###############################################################
#  Generated by:      Cadence Innovus 21.35-s114_1
#  OS:                Linux x86_64(Host ID pc231.ee.hacettepe.edu.tr)
#  Generated on:      Wed Dec 24 15:45:05 2025
#  Design:            pwm_accelerator_macro
#  Command:           write_lef_abstract -5.7 outputs/pwm_accelerator_macro/pwm_accelerator_macro.lef
###############################################################

VERSION 5.7 ;

BUSBITCHARS "[]" ;
DIVIDERCHAR "/" ;

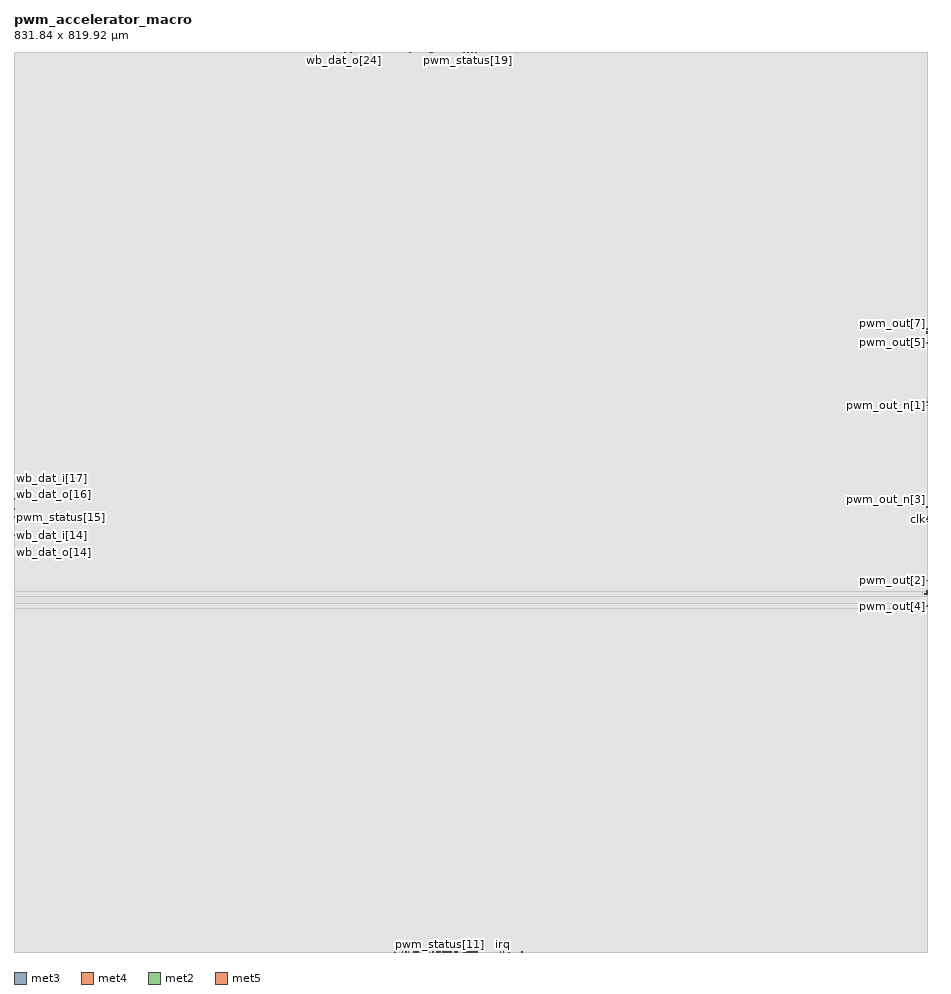
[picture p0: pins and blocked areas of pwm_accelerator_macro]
MACRO pwm_accelerator_macro
  CLASS BLOCK ;
  SIZE 831.840000 BY 819.920000 ;
  FOREIGN pwm_accelerator_macro 0.000000 0.000000 ;
  ORIGIN 0 0 ;
  SYMMETRY X Y R90 ;
  PIN clk
    DIRECTION INPUT ;
    USE SIGNAL ;
    PORT
      LAYER met3 ;
        RECT 831.040000 393.670000 831.840000 393.970000 ;
    END
  END clk
  PIN rst_n
    DIRECTION INPUT ;
    USE SIGNAL ;
    PORT
      LAYER met3 ;
        RECT 831.040000 394.890000 831.840000 395.190000 ;
    END
  END rst_n
  PIN wb_adr_i[31]
    DIRECTION INPUT ;
    USE SIGNAL ;
    PORT
      LAYER met4 ;
        RECT 413.370000 819.120000 413.670000 819.920000 ;
    END
  END wb_adr_i[31]
  PIN wb_adr_i[30]
    DIRECTION INPUT ;
    USE SIGNAL ;
    PORT
      LAYER met4 ;
        RECT 413.370000 0.000000 413.670000 0.800000 ;
    END
  END wb_adr_i[30]
  PIN wb_adr_i[29]
    DIRECTION INPUT ;
    USE SIGNAL ;
    PORT
      LAYER met4 ;
        RECT 418.290000 819.120000 418.590000 819.920000 ;
    END
  END wb_adr_i[29]
  PIN wb_adr_i[28]
    DIRECTION INPUT ;
    USE SIGNAL ;
    PORT
      LAYER met4 ;
        RECT 418.290000 0.000000 418.590000 0.800000 ;
    END
  END wb_adr_i[28]
  PIN wb_adr_i[27]
    DIRECTION INPUT ;
    USE SIGNAL ;
    PORT
      LAYER met2 ;
        RECT 412.970000 819.435000 413.110000 819.920000 ;
    END
  END wb_adr_i[27]
  PIN wb_adr_i[26]
    DIRECTION INPUT ;
    USE SIGNAL ;
    PORT
      LAYER met2 ;
        RECT 418.730000 819.435000 418.870000 819.920000 ;
    END
  END wb_adr_i[26]
  PIN wb_adr_i[25]
    DIRECTION INPUT ;
    USE SIGNAL ;
    PORT
      LAYER met2 ;
        RECT 412.970000 0.000000 413.110000 0.485000 ;
    END
  END wb_adr_i[25]
  PIN wb_adr_i[24]
    DIRECTION INPUT ;
    USE SIGNAL ;
    PORT
      LAYER met2 ;
        RECT 418.730000 0.000000 418.870000 0.485000 ;
    END
  END wb_adr_i[24]
  PIN wb_adr_i[23]
    DIRECTION INPUT ;
    USE SIGNAL ;
    PORT
      LAYER met2 ;
        RECT 412.010000 819.435000 412.150000 819.920000 ;
    END
  END wb_adr_i[23]
  PIN wb_adr_i[22]
    DIRECTION INPUT ;
    USE SIGNAL ;
    PORT
      LAYER met4 ;
        RECT 412.140000 819.120000 412.440000 819.920000 ;
    END
  END wb_adr_i[22]
  PIN wb_adr_i[21]
    DIRECTION INPUT ;
    USE SIGNAL ;
    PORT
      LAYER met2 ;
        RECT 412.010000 0.000000 412.150000 0.485000 ;
    END
  END wb_adr_i[21]
  PIN wb_adr_i[20]
    DIRECTION INPUT ;
    USE SIGNAL ;
    PORT
      LAYER met4 ;
        RECT 412.140000 0.000000 412.440000 0.800000 ;
    END
  END wb_adr_i[20]
  PIN wb_adr_i[19]
    DIRECTION INPUT ;
    USE SIGNAL ;
    PORT
      LAYER met2 ;
        RECT 419.690000 819.435000 419.830000 819.920000 ;
    END
  END wb_adr_i[19]
  PIN wb_adr_i[18]
    DIRECTION INPUT ;
    USE SIGNAL ;
    PORT
      LAYER met4 ;
        RECT 419.520000 819.120000 419.820000 819.920000 ;
    END
  END wb_adr_i[18]
  PIN wb_adr_i[17]
    DIRECTION INPUT ;
    USE SIGNAL ;
    PORT
      LAYER met2 ;
        RECT 419.690000 0.000000 419.830000 0.485000 ;
    END
  END wb_adr_i[17]
  PIN wb_adr_i[16]
    DIRECTION INPUT ;
    USE SIGNAL ;
    PORT
      LAYER met4 ;
        RECT 419.520000 0.000000 419.820000 0.800000 ;
    END
  END wb_adr_i[16]
  PIN wb_adr_i[15]
    DIRECTION INPUT ;
    USE SIGNAL ;
    PORT
      LAYER met2 ;
        RECT 411.050000 819.435000 411.190000 819.920000 ;
    END
  END wb_adr_i[15]
  PIN wb_adr_i[14]
    DIRECTION INPUT ;
    USE SIGNAL ;
    PORT
      LAYER met2 ;
        RECT 420.650000 819.435000 420.790000 819.920000 ;
    END
  END wb_adr_i[14]
  PIN wb_adr_i[13]
    DIRECTION INPUT ;
    USE SIGNAL ;
    PORT
      LAYER met2 ;
        RECT 411.050000 0.000000 411.190000 0.485000 ;
    END
  END wb_adr_i[13]
  PIN wb_adr_i[12]
    DIRECTION INPUT ;
    USE SIGNAL ;
    PORT
      LAYER met2 ;
        RECT 420.650000 0.000000 420.790000 0.485000 ;
    END
  END wb_adr_i[12]
  PIN wb_adr_i[11]
    DIRECTION INPUT ;
    USE SIGNAL ;
    PORT
      LAYER met4 ;
        RECT 410.910000 819.120000 411.210000 819.920000 ;
    END
  END wb_adr_i[11]
  PIN wb_adr_i[10]
    DIRECTION INPUT ;
    USE SIGNAL ;
    PORT
      LAYER met4 ;
        RECT 410.910000 0.000000 411.210000 0.800000 ;
    END
  END wb_adr_i[10]
  PIN wb_adr_i[9]
    DIRECTION INPUT ;
    USE SIGNAL ;
    PORT
      LAYER met4 ;
        RECT 420.750000 819.120000 421.050000 819.920000 ;
    END
  END wb_adr_i[9]
  PIN wb_adr_i[8]
    DIRECTION INPUT ;
    USE SIGNAL ;
    PORT
      LAYER met4 ;
        RECT 420.750000 0.000000 421.050000 0.800000 ;
    END
  END wb_adr_i[8]
  PIN wb_adr_i[7]
    DIRECTION INPUT ;
    USE SIGNAL ;
    PORT
      LAYER met2 ;
        RECT 403.370000 0.000000 403.510000 0.485000 ;
    END
  END wb_adr_i[7]
  PIN wb_adr_i[6]
    DIRECTION INPUT ;
    USE SIGNAL ;
    PORT
      LAYER met2 ;
        RECT 410.090000 0.000000 410.230000 0.485000 ;
    END
  END wb_adr_i[6]
  PIN wb_adr_i[5]
    DIRECTION INPUT ;
    USE SIGNAL ;
    PORT
      LAYER met4 ;
        RECT 402.915000 0.000000 403.215000 0.800000 ;
    END
  END wb_adr_i[5]
  PIN wb_adr_i[4]
    DIRECTION INPUT ;
    USE SIGNAL ;
    PORT
      LAYER met4 ;
        RECT 409.680000 0.000000 409.980000 0.800000 ;
    END
  END wb_adr_i[4]
  PIN wb_adr_i[3]
    DIRECTION INPUT ;
    USE SIGNAL ;
    PORT
      LAYER met2 ;
        RECT 402.410000 0.000000 402.550000 0.485000 ;
    END
  END wb_adr_i[3]
  PIN wb_adr_i[2]
    DIRECTION INPUT ;
    USE SIGNAL ;
    PORT
      LAYER met4 ;
        RECT 394.920000 0.000000 395.220000 0.800000 ;
    END
  END wb_adr_i[2]
  PIN wb_adr_i[1]
    DIRECTION INPUT ;
    USE SIGNAL ;
    PORT
      LAYER met2 ;
        RECT 410.090000 819.435000 410.230000 819.920000 ;
    END
  END wb_adr_i[1]
  PIN wb_adr_i[0]
    DIRECTION INPUT ;
    USE SIGNAL ;
    PORT
      LAYER met2 ;
        RECT 421.610000 819.435000 421.750000 819.920000 ;
    END
  END wb_adr_i[0]
  PIN wb_dat_o[31]
    DIRECTION OUTPUT ;
    USE SIGNAL ;
    PORT
      LAYER met2 ;
        RECT 369.290000 819.435000 369.430000 819.920000 ;
    END
  END wb_dat_o[31]
  PIN wb_dat_o[30]
    DIRECTION OUTPUT ;
    USE SIGNAL ;
    PORT
      LAYER met2 ;
        RECT 306.890000 819.435000 307.030000 819.920000 ;
    END
  END wb_dat_o[30]
  PIN wb_dat_o[29]
    DIRECTION OUTPUT ;
    USE SIGNAL ;
    PORT
      LAYER met2 ;
        RECT 301.130000 819.435000 301.270000 819.920000 ;
    END
  END wb_dat_o[29]
  PIN wb_dat_o[28]
    DIRECTION OUTPUT ;
    USE SIGNAL ;
    PORT
      LAYER met2 ;
        RECT 312.650000 819.435000 312.790000 819.920000 ;
    END
  END wb_dat_o[28]
  PIN wb_dat_o[27]
    DIRECTION OUTPUT ;
    USE SIGNAL ;
    PORT
      LAYER met4 ;
        RECT 311.895000 819.120000 312.195000 819.920000 ;
    END
  END wb_dat_o[27]
  PIN wb_dat_o[26]
    DIRECTION OUTPUT ;
    USE SIGNAL ;
    PORT
      LAYER met2 ;
        RECT 304.010000 819.435000 304.150000 819.920000 ;
    END
  END wb_dat_o[26]
  PIN wb_dat_o[25]
    DIRECTION OUTPUT ;
    USE SIGNAL ;
    PORT
      LAYER met4 ;
        RECT 301.440000 819.120000 301.740000 819.920000 ;
    END
  END wb_dat_o[25]
  PIN wb_dat_o[24]
    DIRECTION OUTPUT ;
    USE SIGNAL ;
    PORT
      LAYER met2 ;
        RECT 300.170000 819.435000 300.310000 819.920000 ;
    END
  END wb_dat_o[24]
  PIN wb_dat_o[23]
    DIRECTION OUTPUT ;
    USE SIGNAL ;
    PORT
      LAYER met2 ;
        RECT 365.930000 819.435000 366.070000 819.920000 ;
    END
  END wb_dat_o[23]
  PIN wb_dat_o[22]
    DIRECTION OUTPUT ;
    USE SIGNAL ;
    PORT
      LAYER met2 ;
        RECT 371.210000 819.435000 371.350000 819.920000 ;
    END
  END wb_dat_o[22]
  PIN wb_dat_o[21]
    DIRECTION OUTPUT ;
    USE SIGNAL ;
    PORT
      LAYER met2 ;
        RECT 362.090000 819.435000 362.230000 819.920000 ;
    END
  END wb_dat_o[21]
  PIN wb_dat_o[20]
    DIRECTION OUTPUT ;
    USE SIGNAL ;
    PORT
      LAYER met2 ;
        RECT 361.130000 819.435000 361.270000 819.920000 ;
    END
  END wb_dat_o[20]
  PIN wb_dat_o[19]
    DIRECTION OUTPUT ;
    USE SIGNAL ;
    PORT
      LAYER met2 ;
        RECT 366.890000 819.435000 367.030000 819.920000 ;
    END
  END wb_dat_o[19]
  PIN wb_dat_o[18]
    DIRECTION OUTPUT ;
    USE SIGNAL ;
    PORT
      LAYER met4 ;
        RECT 360.480000 819.120000 360.780000 819.920000 ;
    END
  END wb_dat_o[18]
  PIN wb_dat_o[17]
    DIRECTION OUTPUT ;
    USE SIGNAL ;
    PORT
      LAYER met3 ;
        RECT 0.000000 435.760000 0.800000 436.060000 ;
    END
  END wb_dat_o[17]
  PIN wb_dat_o[16]
    DIRECTION OUTPUT ;
    USE SIGNAL ;
    PORT
      LAYER met3 ;
        RECT 0.000000 416.850000 0.800000 417.150000 ;
    END
  END wb_dat_o[16]
  PIN wb_dat_o[15]
    DIRECTION OUTPUT ;
    USE SIGNAL ;
    PORT
      LAYER met3 ;
        RECT 0.000000 393.670000 0.800000 393.970000 ;
    END
  END wb_dat_o[15]
  PIN wb_dat_o[14]
    DIRECTION OUTPUT ;
    USE SIGNAL ;
    PORT
      LAYER met3 ;
        RECT 0.000000 363.780000 0.800000 364.080000 ;
    END
  END wb_dat_o[14]
  PIN wb_dat_o[13]
    DIRECTION OUTPUT ;
    USE SIGNAL ;
    PORT
      LAYER met2 ;
        RECT 373.610000 0.000000 373.750000 0.485000 ;
    END
  END wb_dat_o[13]
  PIN wb_dat_o[12]
    DIRECTION OUTPUT ;
    USE SIGNAL ;
    PORT
      LAYER met2 ;
        RECT 382.250000 0.000000 382.390000 0.485000 ;
    END
  END wb_dat_o[12]
  PIN wb_dat_o[11]
    DIRECTION OUTPUT ;
    USE SIGNAL ;
    PORT
      LAYER met2 ;
        RECT 374.570000 0.000000 374.710000 0.485000 ;
    END
  END wb_dat_o[11]
  PIN wb_dat_o[10]
    DIRECTION OUTPUT ;
    USE SIGNAL ;
    PORT
      LAYER met2 ;
        RECT 370.730000 0.000000 370.870000 0.485000 ;
    END
  END wb_dat_o[10]
  PIN wb_dat_o[9]
    DIRECTION OUTPUT ;
    USE SIGNAL ;
    PORT
      LAYER met2 ;
        RECT 376.490000 0.000000 376.630000 0.485000 ;
    END
  END wb_dat_o[9]
  PIN wb_dat_o[8]
    DIRECTION OUTPUT ;
    USE SIGNAL ;
    PORT
      LAYER met2 ;
        RECT 378.410000 0.000000 378.550000 0.485000 ;
    END
  END wb_dat_o[8]
  PIN wb_dat_o[7]
    DIRECTION OUTPUT ;
    USE SIGNAL ;
    PORT
      LAYER met2 ;
        RECT 372.650000 0.000000 372.790000 0.485000 ;
    END
  END wb_dat_o[7]
  PIN wb_dat_o[6]
    DIRECTION OUTPUT ;
    USE SIGNAL ;
    PORT
      LAYER met2 ;
        RECT 366.410000 0.000000 366.550000 0.485000 ;
    END
  END wb_dat_o[6]
  PIN wb_dat_o[5]
    DIRECTION OUTPUT ;
    USE SIGNAL ;
    PORT
      LAYER met4 ;
        RECT 365.400000 0.000000 365.700000 0.800000 ;
    END
  END wb_dat_o[5]
  PIN wb_dat_o[4]
    DIRECTION OUTPUT ;
    USE SIGNAL ;
    PORT
      LAYER met2 ;
        RECT 364.010000 0.000000 364.150000 0.485000 ;
    END
  END wb_dat_o[4]
  PIN wb_dat_o[3]
    DIRECTION OUTPUT ;
    USE SIGNAL ;
    PORT
      LAYER met4 ;
        RECT 356.790000 0.000000 357.090000 0.800000 ;
    END
  END wb_dat_o[3]
  PIN wb_dat_o[2]
    DIRECTION OUTPUT ;
    USE SIGNAL ;
    PORT
      LAYER met4 ;
        RECT 372.165000 0.000000 372.465000 0.800000 ;
    END
  END wb_dat_o[2]
  PIN wb_dat_o[1]
    DIRECTION OUTPUT ;
    USE SIGNAL ;
    PORT
      LAYER met4 ;
        RECT 376.470000 0.000000 376.770000 0.800000 ;
    END
  END wb_dat_o[1]
  PIN wb_dat_o[0]
    DIRECTION OUTPUT ;
    USE SIGNAL ;
    PORT
      LAYER met4 ;
        RECT 364.170000 0.000000 364.470000 0.800000 ;
    END
  END wb_dat_o[0]
  PIN wb_dat_i[31]
    DIRECTION INPUT ;
    USE SIGNAL ;
    PORT
      LAYER met2 ;
        RECT 377.930000 819.435000 378.070000 819.920000 ;
    END
  END wb_dat_i[31]
  PIN wb_dat_i[30]
    DIRECTION INPUT ;
    USE SIGNAL ;
    PORT
      LAYER met4 ;
        RECT 377.700000 819.120000 378.000000 819.920000 ;
    END
  END wb_dat_i[30]
  PIN wb_dat_i[29]
    DIRECTION INPUT ;
    USE SIGNAL ;
    PORT
      LAYER met2 ;
        RECT 379.370000 819.435000 379.510000 819.920000 ;
    END
  END wb_dat_i[29]
  PIN wb_dat_i[28]
    DIRECTION INPUT ;
    USE SIGNAL ;
    PORT
      LAYER met2 ;
        RECT 381.290000 819.435000 381.430000 819.920000 ;
    END
  END wb_dat_i[28]
  PIN wb_dat_i[27]
    DIRECTION INPUT ;
    USE SIGNAL ;
    PORT
      LAYER met4 ;
        RECT 378.930000 819.120000 379.230000 819.920000 ;
    END
  END wb_dat_i[27]
  PIN wb_dat_i[26]
    DIRECTION INPUT ;
    USE SIGNAL ;
    PORT
      LAYER met4 ;
        RECT 380.775000 819.120000 381.075000 819.920000 ;
    END
  END wb_dat_i[26]
  PIN wb_dat_i[25]
    DIRECTION INPUT ;
    USE SIGNAL ;
    PORT
      LAYER met2 ;
        RECT 376.970000 819.435000 377.110000 819.920000 ;
    END
  END wb_dat_i[25]
  PIN wb_dat_i[24]
    DIRECTION INPUT ;
    USE SIGNAL ;
    PORT
      LAYER met2 ;
        RECT 380.330000 819.435000 380.470000 819.920000 ;
    END
  END wb_dat_i[24]
  PIN wb_dat_i[23]
    DIRECTION INPUT ;
    USE SIGNAL ;
    PORT
      LAYER met4 ;
        RECT 376.470000 819.120000 376.770000 819.920000 ;
    END
  END wb_dat_i[23]
  PIN wb_dat_i[22]
    DIRECTION INPUT ;
    USE SIGNAL ;
    PORT
      LAYER met2 ;
        RECT 394.250000 819.435000 394.390000 819.920000 ;
    END
  END wb_dat_i[22]
  PIN wb_dat_i[21]
    DIRECTION INPUT ;
    USE SIGNAL ;
    PORT
      LAYER met2 ;
        RECT 372.170000 819.435000 372.310000 819.920000 ;
    END
  END wb_dat_i[21]
  PIN wb_dat_i[20]
    DIRECTION INPUT ;
    USE SIGNAL ;
    PORT
      LAYER met4 ;
        RECT 372.165000 819.120000 372.465000 819.920000 ;
    END
  END wb_dat_i[20]
  PIN wb_dat_i[19]
    DIRECTION INPUT ;
    USE SIGNAL ;
    PORT
      LAYER met2 ;
        RECT 373.610000 819.435000 373.750000 819.920000 ;
    END
  END wb_dat_i[19]
  PIN wb_dat_i[18]
    DIRECTION INPUT ;
    USE SIGNAL ;
    PORT
      LAYER met2 ;
        RECT 375.530000 819.435000 375.670000 819.920000 ;
    END
  END wb_dat_i[18]
  PIN wb_dat_i[17]
    DIRECTION INPUT ;
    USE SIGNAL ;
    PORT
      LAYER met3 ;
        RECT 0.000000 431.490000 0.800000 431.790000 ;
    END
  END wb_dat_i[17]
  PIN wb_dat_i[16]
    DIRECTION INPUT ;
    USE SIGNAL ;
    PORT
      LAYER met3 ;
        RECT 0.000000 412.580000 0.800000 412.880000 ;
    END
  END wb_dat_i[16]
  PIN wb_dat_i[15]
    DIRECTION INPUT ;
    USE SIGNAL ;
    PORT
      LAYER met3 ;
        RECT 0.000000 403.430000 0.800000 403.730000 ;
    END
  END wb_dat_i[15]
  PIN wb_dat_i[14]
    DIRECTION INPUT ;
    USE SIGNAL ;
    PORT
      LAYER met3 ;
        RECT 0.000000 379.640000 0.800000 379.940000 ;
    END
  END wb_dat_i[14]
  PIN wb_dat_i[13]
    DIRECTION INPUT ;
    USE SIGNAL ;
    PORT
      LAYER met2 ;
        RECT 409.130000 0.000000 409.270000 0.485000 ;
    END
  END wb_dat_i[13]
  PIN wb_dat_i[12]
    DIRECTION INPUT ;
    USE SIGNAL ;
    PORT
      LAYER met2 ;
        RECT 404.330000 0.000000 404.470000 0.485000 ;
    END
  END wb_dat_i[12]
  PIN wb_dat_i[11]
    DIRECTION INPUT ;
    USE SIGNAL ;
    PORT
      LAYER met2 ;
        RECT 367.370000 0.000000 367.510000 0.485000 ;
    END
  END wb_dat_i[11]
  PIN wb_dat_i[10]
    DIRECTION INPUT ;
    USE SIGNAL ;
    PORT
      LAYER met2 ;
        RECT 364.970000 0.000000 365.110000 0.485000 ;
    END
  END wb_dat_i[10]
  PIN wb_dat_i[9]
    DIRECTION INPUT ;
    USE SIGNAL ;
    PORT
      LAYER met4 ;
        RECT 366.630000 0.000000 366.930000 0.800000 ;
    END
  END wb_dat_i[9]
  PIN wb_dat_i[8]
    DIRECTION INPUT ;
    USE SIGNAL ;
    PORT
      LAYER met4 ;
        RECT 367.860000 0.000000 368.160000 0.800000 ;
    END
  END wb_dat_i[8]
  PIN wb_dat_i[7]
    DIRECTION INPUT ;
    USE SIGNAL ;
    PORT
      LAYER met2 ;
        RECT 359.210000 0.000000 359.350000 0.485000 ;
    END
  END wb_dat_i[7]
  PIN wb_dat_i[6]
    DIRECTION INPUT ;
    USE SIGNAL ;
    PORT
      LAYER met2 ;
        RECT 347.690000 0.000000 347.830000 0.485000 ;
    END
  END wb_dat_i[6]
  PIN wb_dat_i[5]
    DIRECTION INPUT ;
    USE SIGNAL ;
    PORT
      LAYER met2 ;
        RECT 357.290000 0.000000 357.430000 0.485000 ;
    END
  END wb_dat_i[5]
  PIN wb_dat_i[4]
    DIRECTION INPUT ;
    USE SIGNAL ;
    PORT
      LAYER met2 ;
        RECT 346.250000 0.000000 346.390000 0.485000 ;
    END
  END wb_dat_i[4]
  PIN wb_dat_i[3]
    DIRECTION INPUT ;
    USE SIGNAL ;
    PORT
      LAYER met2 ;
        RECT 353.930000 0.000000 354.070000 0.485000 ;
    END
  END wb_dat_i[3]
  PIN wb_dat_i[2]
    DIRECTION INPUT ;
    USE SIGNAL ;
    PORT
      LAYER met2 ;
        RECT 462.890000 0.000000 463.030000 0.485000 ;
    END
  END wb_dat_i[2]
  PIN wb_dat_i[1]
    DIRECTION INPUT ;
    USE SIGNAL ;
    PORT
      LAYER met2 ;
        RECT 461.930000 0.000000 462.070000 0.485000 ;
    END
  END wb_dat_i[1]
  PIN wb_dat_i[0]
    DIRECTION INPUT ;
    USE SIGNAL ;
    PORT
      LAYER met2 ;
        RECT 443.210000 0.000000 443.350000 0.485000 ;
    END
  END wb_dat_i[0]
  PIN wb_we_i
    DIRECTION INPUT ;
    USE SIGNAL ;
    PORT
      LAYER met2 ;
        RECT 398.090000 0.000000 398.230000 0.485000 ;
    END
  END wb_we_i
  PIN wb_sel_i[3]
    DIRECTION INPUT ;
    USE SIGNAL ;
    PORT
      LAYER met2 ;
        RECT 421.610000 0.000000 421.750000 0.485000 ;
    END
  END wb_sel_i[3]
  PIN wb_sel_i[2]
    DIRECTION INPUT ;
    USE SIGNAL ;
    PORT
      LAYER met4 ;
        RECT 409.680000 819.120000 409.980000 819.920000 ;
    END
  END wb_sel_i[2]
  PIN wb_sel_i[1]
    DIRECTION INPUT ;
    USE SIGNAL ;
    PORT
      LAYER met4 ;
        RECT 421.980000 819.120000 422.280000 819.920000 ;
    END
  END wb_sel_i[1]
  PIN wb_sel_i[0]
    DIRECTION INPUT ;
    USE SIGNAL ;
    PORT
      LAYER met4 ;
        RECT 421.980000 0.000000 422.280000 0.800000 ;
    END
  END wb_sel_i[0]
  PIN wb_cyc_i
    DIRECTION INPUT ;
    USE SIGNAL ;
    PORT
      LAYER met2 ;
        RECT 400.970000 0.000000 401.110000 0.485000 ;
    END
  END wb_cyc_i
  PIN wb_stb_i
    DIRECTION INPUT ;
    USE SIGNAL ;
    PORT
      LAYER met4 ;
        RECT 386.310000 0.000000 386.610000 0.800000 ;
    END
  END wb_stb_i
  PIN wb_ack_o
    DIRECTION OUTPUT ;
    USE SIGNAL ;
    PORT
      LAYER met4 ;
        RECT 370.935000 0.000000 371.235000 0.800000 ;
    END
  END wb_ack_o
  PIN wb_err_o
    DIRECTION OUTPUT ;
    USE SIGNAL ;
    PORT
      LAYER met3 ;
        RECT 0.000000 409.530000 0.800000 409.830000 ;
    END
  END wb_err_o
  PIN pwm_out[7]
    DIRECTION OUTPUT ;
    USE SIGNAL ;
    PORT
      LAYER met3 ;
        RECT 831.040000 565.080000 831.840000 565.380000 ;
    END
  END pwm_out[7]
  PIN pwm_out[6]
    DIRECTION OUTPUT ;
    USE SIGNAL ;
    PORT
      LAYER met3 ;
        RECT 831.040000 327.790000 831.840000 328.090000 ;
    END
  END pwm_out[6]
  PIN pwm_out[5]
    DIRECTION OUTPUT ;
    USE SIGNAL ;
    PORT
      LAYER met3 ;
        RECT 831.040000 554.710000 831.840000 555.010000 ;
    END
  END pwm_out[5]
  PIN pwm_out[4]
    DIRECTION OUTPUT ;
    USE SIGNAL ;
    PORT
      LAYER met3 ;
        RECT 831.040000 314.980000 831.840000 315.280000 ;
    END
  END pwm_out[4]
  PIN pwm_out[3]
    DIRECTION OUTPUT ;
    USE SIGNAL ;
    PORT
      LAYER met3 ;
        RECT 831.040000 391.840000 831.840000 392.140000 ;
    END
  END pwm_out[3]
  PIN pwm_out[2]
    DIRECTION OUTPUT ;
    USE SIGNAL ;
    PORT
      LAYER met3 ;
        RECT 831.040000 338.160000 831.840000 338.460000 ;
    END
  END pwm_out[2]
  PIN pwm_out[1]
    DIRECTION OUTPUT ;
    USE SIGNAL ;
    PORT
      LAYER met3 ;
        RECT 831.040000 501.030000 831.840000 501.330000 ;
    END
  END pwm_out[1]
  PIN pwm_out[0]
    DIRECTION OUTPUT ;
    USE SIGNAL ;
    PORT
      LAYER met5 ;
        RECT 829.340000 314.330000 831.840000 315.930000 ;
    END
  END pwm_out[0]
  PIN pwm_out_n[7]
    DIRECTION OUTPUT ;
    USE SIGNAL ;
    PORT
      LAYER met3 ;
        RECT 831.040000 563.860000 831.840000 564.160000 ;
    END
  END pwm_out_n[7]
  PIN pwm_out_n[6]
    DIRECTION OUTPUT ;
    USE SIGNAL ;
    PORT
      LAYER met3 ;
        RECT 831.040000 325.350000 831.840000 325.650000 ;
    END
  END pwm_out_n[6]
  PIN pwm_out_n[5]
    DIRECTION OUTPUT ;
    USE SIGNAL ;
    PORT
      LAYER met3 ;
        RECT 831.040000 567.520000 831.840000 567.820000 ;
    END
  END pwm_out_n[5]
  PIN pwm_out_n[4]
    DIRECTION OUTPUT ;
    USE SIGNAL ;
    PORT
      LAYER met3 ;
        RECT 831.040000 329.010000 831.840000 329.310000 ;
    END
  END pwm_out_n[4]
  PIN pwm_out_n[3]
    DIRECTION OUTPUT ;
    USE SIGNAL ;
    PORT
      LAYER met3 ;
        RECT 831.040000 405.260000 831.840000 405.560000 ;
    END
  END pwm_out_n[3]
  PIN pwm_out_n[2]
    DIRECTION OUTPUT ;
    USE SIGNAL ;
    PORT
      LAYER met3 ;
        RECT 831.040000 326.570000 831.840000 326.870000 ;
    END
  END pwm_out_n[2]
  PIN pwm_out_n[1]
    DIRECTION OUTPUT ;
    USE SIGNAL ;
    PORT
      LAYER met3 ;
        RECT 831.040000 497.980000 831.840000 498.280000 ;
    END
  END pwm_out_n[1]
  PIN pwm_out_n[0]
    DIRECTION OUTPUT ;
    USE SIGNAL ;
    PORT
      LAYER met5 ;
        RECT 829.340000 325.310000 831.840000 326.910000 ;
    END
  END pwm_out_n[0]
  PIN irq
    DIRECTION OUTPUT ;
    USE SIGNAL ;
    PORT
      LAYER met2 ;
        RECT 445.610000 0.000000 445.750000 0.485000 ;
    END
  END irq
  PIN pwm_sync_out
    DIRECTION OUTPUT ;
    USE SIGNAL ;
    PORT
      LAYER met2 ;
        RECT 450.890000 0.000000 451.030000 0.485000 ;
    END
  END pwm_sync_out
  PIN pwm_sync_in
    DIRECTION INPUT ;
    USE SIGNAL ;
    PORT
      LAYER met3 ;
        RECT 831.040000 396.110000 831.840000 396.410000 ;
    END
  END pwm_sync_in
  PIN pwm_status[31]
    DIRECTION OUTPUT ;
    USE SIGNAL ;
    PORT
      LAYER met2 ;
        RECT 415.850000 819.435000 415.990000 819.920000 ;
    END
  END pwm_status[31]
  PIN pwm_status[30]
    DIRECTION OUTPUT ;
    USE SIGNAL ;
    PORT
      LAYER met2 ;
        RECT 415.850000 0.000000 415.990000 0.485000 ;
    END
  END pwm_status[30]
  PIN pwm_status[29]
    DIRECTION OUTPUT ;
    USE SIGNAL ;
    PORT
      LAYER met4 ;
        RECT 415.830000 819.120000 416.130000 819.920000 ;
    END
  END pwm_status[29]
  PIN pwm_status[28]
    DIRECTION OUTPUT ;
    USE SIGNAL ;
    PORT
      LAYER met4 ;
        RECT 415.830000 0.000000 416.130000 0.800000 ;
    END
  END pwm_status[28]
  PIN pwm_status[27]
    DIRECTION OUTPUT ;
    USE SIGNAL ;
    PORT
      LAYER met2 ;
        RECT 414.890000 819.435000 415.030000 819.920000 ;
    END
  END pwm_status[27]
  PIN pwm_status[26]
    DIRECTION OUTPUT ;
    USE SIGNAL ;
    PORT
      LAYER met2 ;
        RECT 416.810000 819.435000 416.950000 819.920000 ;
    END
  END pwm_status[26]
  PIN pwm_status[25]
    DIRECTION OUTPUT ;
    USE SIGNAL ;
    PORT
      LAYER met2 ;
        RECT 414.890000 0.000000 415.030000 0.485000 ;
    END
  END pwm_status[25]
  PIN pwm_status[24]
    DIRECTION OUTPUT ;
    USE SIGNAL ;
    PORT
      LAYER met2 ;
        RECT 416.810000 0.000000 416.950000 0.485000 ;
    END
  END pwm_status[24]
  PIN pwm_status[23]
    DIRECTION OUTPUT ;
    USE SIGNAL ;
    PORT
      LAYER met4 ;
        RECT 414.600000 819.120000 414.900000 819.920000 ;
    END
  END pwm_status[23]
  PIN pwm_status[22]
    DIRECTION OUTPUT ;
    USE SIGNAL ;
    PORT
      LAYER met4 ;
        RECT 414.600000 0.000000 414.900000 0.800000 ;
    END
  END pwm_status[22]
  PIN pwm_status[21]
    DIRECTION OUTPUT ;
    USE SIGNAL ;
    PORT
      LAYER met4 ;
        RECT 417.060000 819.120000 417.360000 819.920000 ;
    END
  END pwm_status[21]
  PIN pwm_status[20]
    DIRECTION OUTPUT ;
    USE SIGNAL ;
    PORT
      LAYER met4 ;
        RECT 417.060000 0.000000 417.360000 0.800000 ;
    END
  END pwm_status[20]
  PIN pwm_status[19]
    DIRECTION OUTPUT ;
    USE SIGNAL ;
    PORT
      LAYER met2 ;
        RECT 413.930000 819.435000 414.070000 819.920000 ;
    END
  END pwm_status[19]
  PIN pwm_status[18]
    DIRECTION OUTPUT ;
    USE SIGNAL ;
    PORT
      LAYER met2 ;
        RECT 417.770000 819.435000 417.910000 819.920000 ;
    END
  END pwm_status[18]
  PIN pwm_status[17]
    DIRECTION OUTPUT ;
    USE SIGNAL ;
    PORT
      LAYER met2 ;
        RECT 413.930000 0.000000 414.070000 0.485000 ;
    END
  END pwm_status[17]
  PIN pwm_status[16]
    DIRECTION OUTPUT ;
    USE SIGNAL ;
    PORT
      LAYER met2 ;
        RECT 417.770000 0.000000 417.910000 0.485000 ;
    END
  END pwm_status[16]
  PIN pwm_status[15]
    DIRECTION OUTPUT ;
    USE SIGNAL ;
    PORT
      LAYER met3 ;
        RECT 0.000000 396.110000 0.800000 396.410000 ;
    END
  END pwm_status[15]
  PIN pwm_status[14]
    DIRECTION OUTPUT ;
    USE SIGNAL ;
    PORT
      LAYER met2 ;
        RECT 391.850000 0.000000 391.990000 0.485000 ;
    END
  END pwm_status[14]
  PIN pwm_status[13]
    DIRECTION OUTPUT ;
    USE SIGNAL ;
    PORT
      LAYER met2 ;
        RECT 394.250000 0.000000 394.390000 0.485000 ;
    END
  END pwm_status[13]
  PIN pwm_status[12]
    DIRECTION OUTPUT ;
    USE SIGNAL ;
    PORT
      LAYER met2 ;
        RECT 392.810000 0.000000 392.950000 0.485000 ;
    END
  END pwm_status[12]
  PIN pwm_status[11]
    DIRECTION OUTPUT ;
    USE SIGNAL ;
    PORT
      LAYER met2 ;
        RECT 388.010000 0.000000 388.150000 0.485000 ;
    END
  END pwm_status[11]
  PIN pwm_status[10]
    DIRECTION OUTPUT ;
    USE SIGNAL ;
    PORT
      LAYER met2 ;
        RECT 384.650000 0.000000 384.790000 0.485000 ;
    END
  END pwm_status[10]
  PIN pwm_status[9]
    DIRECTION OUTPUT ;
    USE SIGNAL ;
    PORT
      LAYER met2 ;
        RECT 386.090000 0.000000 386.230000 0.485000 ;
    END
  END pwm_status[9]
  PIN pwm_status[8]
    DIRECTION OUTPUT ;
    USE SIGNAL ;
    PORT
      LAYER met4 ;
        RECT 385.080000 0.000000 385.380000 0.800000 ;
    END
  END pwm_status[8]
  PIN pwm_status[7]
    DIRECTION OUTPUT ;
    USE SIGNAL ;
    PORT
      LAYER met2 ;
        RECT 395.690000 0.000000 395.830000 0.485000 ;
    END
  END pwm_status[7]
  PIN pwm_status[6]
    DIRECTION OUTPUT ;
    USE SIGNAL ;
    PORT
      LAYER met2 ;
        RECT 397.130000 0.000000 397.270000 0.485000 ;
    END
  END pwm_status[6]
  PIN pwm_status[5]
    DIRECTION OUTPUT ;
    USE SIGNAL ;
    PORT
      LAYER met4 ;
        RECT 396.765000 0.000000 397.065000 0.800000 ;
    END
  END pwm_status[5]
  PIN pwm_status[4]
    DIRECTION OUTPUT ;
    USE SIGNAL ;
    PORT
      LAYER met4 ;
        RECT 393.690000 0.000000 393.990000 0.800000 ;
    END
  END pwm_status[4]
  PIN pwm_status[3]
    DIRECTION OUTPUT ;
    USE SIGNAL ;
    PORT
      LAYER met2 ;
        RECT 390.890000 0.000000 391.030000 0.485000 ;
    END
  END pwm_status[3]
  PIN pwm_status[2]
    DIRECTION OUTPUT ;
    USE SIGNAL ;
    PORT
      LAYER met4 ;
        RECT 391.845000 0.000000 392.145000 0.800000 ;
    END
  END pwm_status[2]
  PIN pwm_status[1]
    DIRECTION OUTPUT ;
    USE SIGNAL ;
    PORT
      LAYER met2 ;
        RECT 380.810000 0.000000 380.950000 0.485000 ;
    END
  END pwm_status[1]
  PIN pwm_status[0]
    DIRECTION OUTPUT ;
    USE SIGNAL ;
    PORT
      LAYER met4 ;
        RECT 390.615000 0.000000 390.915000 0.800000 ;
    END
  END pwm_status[0]
  OBS
    LAYER met1 ;
      RECT 0.000000 0.000000 831.840000 819.920000 ;
    LAYER met2 ;
      RECT 421.890000 819.295000 831.840000 819.920000 ;
      RECT 420.930000 819.295000 421.470000 819.920000 ;
      RECT 419.970000 819.295000 420.510000 819.920000 ;
      RECT 419.010000 819.295000 419.550000 819.920000 ;
      RECT 418.050000 819.295000 418.590000 819.920000 ;
      RECT 417.090000 819.295000 417.630000 819.920000 ;
      RECT 416.130000 819.295000 416.670000 819.920000 ;
      RECT 415.170000 819.295000 415.710000 819.920000 ;
      RECT 414.210000 819.295000 414.750000 819.920000 ;
      RECT 413.250000 819.295000 413.790000 819.920000 ;
      RECT 412.290000 819.295000 412.830000 819.920000 ;
      RECT 411.330000 819.295000 411.870000 819.920000 ;
      RECT 410.370000 819.295000 410.910000 819.920000 ;
      RECT 394.530000 819.295000 409.950000 819.920000 ;
      RECT 381.570000 819.295000 394.110000 819.920000 ;
      RECT 380.610000 819.295000 381.150000 819.920000 ;
      RECT 379.650000 819.295000 380.190000 819.920000 ;
      RECT 378.210000 819.295000 379.230000 819.920000 ;
      RECT 377.250000 819.295000 377.790000 819.920000 ;
      RECT 375.810000 819.295000 376.830000 819.920000 ;
      RECT 373.890000 819.295000 375.390000 819.920000 ;
      RECT 372.450000 819.295000 373.470000 819.920000 ;
      RECT 371.490000 819.295000 372.030000 819.920000 ;
      RECT 369.570000 819.295000 371.070000 819.920000 ;
      RECT 367.170000 819.295000 369.150000 819.920000 ;
      RECT 366.210000 819.295000 366.750000 819.920000 ;
      RECT 362.370000 819.295000 365.790000 819.920000 ;
      RECT 361.410000 819.295000 361.950000 819.920000 ;
      RECT 312.930000 819.295000 360.990000 819.920000 ;
      RECT 307.170000 819.295000 312.510000 819.920000 ;
      RECT 304.290000 819.295000 306.750000 819.920000 ;
      RECT 301.410000 819.295000 303.870000 819.920000 ;
      RECT 300.450000 819.295000 300.990000 819.920000 ;
      RECT 0.000000 819.295000 300.030000 819.920000 ;
      RECT 0.000000 0.625000 831.840000 819.295000 ;
      RECT 463.170000 0.000000 831.840000 0.625000 ;
      RECT 462.210000 0.000000 462.750000 0.625000 ;
      RECT 451.170000 0.000000 461.790000 0.625000 ;
      RECT 445.890000 0.000000 450.750000 0.625000 ;
      RECT 443.490000 0.000000 445.470000 0.625000 ;
      RECT 421.890000 0.000000 443.070000 0.625000 ;
      RECT 420.930000 0.000000 421.470000 0.625000 ;
      RECT 419.970000 0.000000 420.510000 0.625000 ;
      RECT 419.010000 0.000000 419.550000 0.625000 ;
      RECT 418.050000 0.000000 418.590000 0.625000 ;
      RECT 417.090000 0.000000 417.630000 0.625000 ;
      RECT 416.130000 0.000000 416.670000 0.625000 ;
      RECT 415.170000 0.000000 415.710000 0.625000 ;
      RECT 414.210000 0.000000 414.750000 0.625000 ;
      RECT 413.250000 0.000000 413.790000 0.625000 ;
      RECT 412.290000 0.000000 412.830000 0.625000 ;
      RECT 411.330000 0.000000 411.870000 0.625000 ;
      RECT 410.370000 0.000000 410.910000 0.625000 ;
      RECT 409.410000 0.000000 409.950000 0.625000 ;
      RECT 404.610000 0.000000 408.990000 0.625000 ;
      RECT 403.650000 0.000000 404.190000 0.625000 ;
      RECT 402.690000 0.000000 403.230000 0.625000 ;
      RECT 401.250000 0.000000 402.270000 0.625000 ;
      RECT 398.370000 0.000000 400.830000 0.625000 ;
      RECT 397.410000 0.000000 397.950000 0.625000 ;
      RECT 395.970000 0.000000 396.990000 0.625000 ;
      RECT 394.530000 0.000000 395.550000 0.625000 ;
      RECT 393.090000 0.000000 394.110000 0.625000 ;
      RECT 392.130000 0.000000 392.670000 0.625000 ;
      RECT 391.170000 0.000000 391.710000 0.625000 ;
      RECT 388.290000 0.000000 390.750000 0.625000 ;
      RECT 386.370000 0.000000 387.870000 0.625000 ;
      RECT 384.930000 0.000000 385.950000 0.625000 ;
      RECT 382.530000 0.000000 384.510000 0.625000 ;
      RECT 381.090000 0.000000 382.110000 0.625000 ;
      RECT 378.690000 0.000000 380.670000 0.625000 ;
      RECT 376.770000 0.000000 378.270000 0.625000 ;
      RECT 374.850000 0.000000 376.350000 0.625000 ;
      RECT 373.890000 0.000000 374.430000 0.625000 ;
      RECT 372.930000 0.000000 373.470000 0.625000 ;
      RECT 371.010000 0.000000 372.510000 0.625000 ;
      RECT 367.650000 0.000000 370.590000 0.625000 ;
      RECT 366.690000 0.000000 367.230000 0.625000 ;
      RECT 365.250000 0.000000 366.270000 0.625000 ;
      RECT 364.290000 0.000000 364.830000 0.625000 ;
      RECT 359.490000 0.000000 363.870000 0.625000 ;
      RECT 357.570000 0.000000 359.070000 0.625000 ;
      RECT 354.210000 0.000000 357.150000 0.625000 ;
      RECT 347.970000 0.000000 353.790000 0.625000 ;
      RECT 346.530000 0.000000 347.550000 0.625000 ;
      RECT 0.000000 0.000000 346.110000 0.625000 ;
    LAYER met3 ;
      RECT 0.000000 568.120000 831.840000 819.920000 ;
      RECT 0.000000 567.220000 830.740000 568.120000 ;
      RECT 0.000000 565.680000 831.840000 567.220000 ;
      RECT 0.000000 564.780000 830.740000 565.680000 ;
      RECT 0.000000 564.460000 831.840000 564.780000 ;
      RECT 0.000000 563.560000 830.740000 564.460000 ;
      RECT 0.000000 555.310000 831.840000 563.560000 ;
      RECT 0.000000 554.410000 830.740000 555.310000 ;
      RECT 0.000000 501.630000 831.840000 554.410000 ;
      RECT 0.000000 500.730000 830.740000 501.630000 ;
      RECT 0.000000 498.580000 831.840000 500.730000 ;
      RECT 0.000000 497.680000 830.740000 498.580000 ;
      RECT 0.000000 436.360000 831.840000 497.680000 ;
      RECT 1.100000 435.460000 831.840000 436.360000 ;
      RECT 0.000000 432.090000 831.840000 435.460000 ;
      RECT 1.100000 431.190000 831.840000 432.090000 ;
      RECT 0.000000 417.450000 831.840000 431.190000 ;
      RECT 1.100000 416.550000 831.840000 417.450000 ;
      RECT 0.000000 413.180000 831.840000 416.550000 ;
      RECT 1.100000 412.280000 831.840000 413.180000 ;
      RECT 0.000000 410.130000 831.840000 412.280000 ;
      RECT 1.100000 409.230000 831.840000 410.130000 ;
      RECT 0.000000 405.860000 831.840000 409.230000 ;
      RECT 0.000000 404.960000 830.740000 405.860000 ;
      RECT 0.000000 404.030000 831.840000 404.960000 ;
      RECT 1.100000 403.130000 831.840000 404.030000 ;
      RECT 0.000000 396.710000 831.840000 403.130000 ;
      RECT 1.100000 395.810000 830.740000 396.710000 ;
      RECT 0.000000 395.490000 831.840000 395.810000 ;
      RECT 0.000000 394.590000 830.740000 395.490000 ;
      RECT 0.000000 394.270000 831.840000 394.590000 ;
      RECT 1.100000 393.370000 830.740000 394.270000 ;
      RECT 0.000000 392.440000 831.840000 393.370000 ;
      RECT 0.000000 391.540000 830.740000 392.440000 ;
      RECT 0.000000 380.240000 831.840000 391.540000 ;
      RECT 1.100000 379.340000 831.840000 380.240000 ;
      RECT 0.000000 364.380000 831.840000 379.340000 ;
      RECT 1.100000 363.480000 831.840000 364.380000 ;
      RECT 0.000000 338.760000 831.840000 363.480000 ;
      RECT 0.000000 337.860000 830.740000 338.760000 ;
      RECT 0.000000 329.610000 831.840000 337.860000 ;
      RECT 0.000000 328.710000 830.740000 329.610000 ;
      RECT 0.000000 328.390000 831.840000 328.710000 ;
      RECT 0.000000 327.490000 830.740000 328.390000 ;
      RECT 0.000000 327.170000 831.840000 327.490000 ;
      RECT 0.000000 326.270000 830.740000 327.170000 ;
      RECT 0.000000 325.950000 831.840000 326.270000 ;
      RECT 0.000000 325.050000 830.740000 325.950000 ;
      RECT 0.000000 315.580000 831.840000 325.050000 ;
      RECT 0.000000 314.680000 830.740000 315.580000 ;
      RECT 0.000000 0.000000 831.840000 314.680000 ;
    LAYER met4 ;
      RECT 422.580000 818.820000 831.840000 819.920000 ;
      RECT 421.350000 818.820000 421.680000 819.920000 ;
      RECT 420.120000 818.820000 420.450000 819.920000 ;
      RECT 418.890000 818.820000 419.220000 819.920000 ;
      RECT 417.660000 818.820000 417.990000 819.920000 ;
      RECT 416.430000 818.820000 416.760000 819.920000 ;
      RECT 415.200000 818.820000 415.530000 819.920000 ;
      RECT 413.970000 818.820000 414.300000 819.920000 ;
      RECT 412.740000 818.820000 413.070000 819.920000 ;
      RECT 411.510000 818.820000 411.840000 819.920000 ;
      RECT 410.280000 818.820000 410.610000 819.920000 ;
      RECT 381.375000 818.820000 409.380000 819.920000 ;
      RECT 379.530000 818.820000 380.475000 819.920000 ;
      RECT 378.300000 818.820000 378.630000 819.920000 ;
      RECT 377.070000 818.820000 377.400000 819.920000 ;
      RECT 372.765000 818.820000 376.170000 819.920000 ;
      RECT 361.080000 818.820000 371.865000 819.920000 ;
      RECT 312.495000 818.820000 360.180000 819.920000 ;
      RECT 302.040000 818.820000 311.595000 819.920000 ;
      RECT 0.000000 818.820000 301.140000 819.920000 ;
      RECT 0.000000 1.100000 831.840000 818.820000 ;
      RECT 422.580000 0.000000 831.840000 1.100000 ;
      RECT 421.350000 0.000000 421.680000 1.100000 ;
      RECT 420.120000 0.000000 420.450000 1.100000 ;
      RECT 418.890000 0.000000 419.220000 1.100000 ;
      RECT 417.660000 0.000000 417.990000 1.100000 ;
      RECT 416.430000 0.000000 416.760000 1.100000 ;
      RECT 415.200000 0.000000 415.530000 1.100000 ;
      RECT 413.970000 0.000000 414.300000 1.100000 ;
      RECT 412.740000 0.000000 413.070000 1.100000 ;
      RECT 411.510000 0.000000 411.840000 1.100000 ;
      RECT 410.280000 0.000000 410.610000 1.100000 ;
      RECT 403.515000 0.000000 409.380000 1.100000 ;
      RECT 397.365000 0.000000 402.615000 1.100000 ;
      RECT 395.520000 0.000000 396.465000 1.100000 ;
      RECT 394.290000 0.000000 394.620000 1.100000 ;
      RECT 392.445000 0.000000 393.390000 1.100000 ;
      RECT 391.215000 0.000000 391.545000 1.100000 ;
      RECT 386.910000 0.000000 390.315000 1.100000 ;
      RECT 385.680000 0.000000 386.010000 1.100000 ;
      RECT 377.070000 0.000000 384.780000 1.100000 ;
      RECT 372.765000 0.000000 376.170000 1.100000 ;
      RECT 371.535000 0.000000 371.865000 1.100000 ;
      RECT 368.460000 0.000000 370.635000 1.100000 ;
      RECT 367.230000 0.000000 367.560000 1.100000 ;
      RECT 366.000000 0.000000 366.330000 1.100000 ;
      RECT 364.770000 0.000000 365.100000 1.100000 ;
      RECT 357.390000 0.000000 363.870000 1.100000 ;
      RECT 0.000000 0.000000 356.490000 1.100000 ;
    LAYER met5 ;
      RECT 0.000000 328.510000 831.840000 819.920000 ;
      RECT 0.000000 323.710000 827.740000 328.510000 ;
      RECT 0.000000 317.530000 831.840000 323.710000 ;
      RECT 0.000000 312.730000 827.740000 317.530000 ;
      RECT 0.000000 0.000000 831.840000 312.730000 ;
  END
END pwm_accelerator_macro

END LIBRARY
